VERSION 5.8 ;
BUSBITCHARS "[]" ;
DIVIDERCHAR "/" ;
UNITS
    DATABASE MICRONS 1000 ;
END UNITS

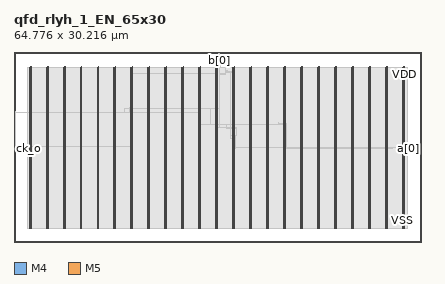
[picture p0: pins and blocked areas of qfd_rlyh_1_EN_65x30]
MACRO qfd_rlyh_1_EN_65x30
  FOREIGN qfd_rlyh_1_EN_65x30 0 0 ;
  CLASS BLOCK ;
  SIZE 64.776 BY 30.216 ;
  PIN a[0]
    DIRECTION INPUT ;
    USE SIGNAL ;
    PORT
      LAYER M4 ;
        RECT  64.692 14.928 64.776 14.952 ;
    END
  END a[0]
  PIN b[0]
    DIRECTION OUTPUT ;
    USE SIGNAL ;
    PORT
      LAYER M5 ;
        RECT  32.592 30.132 32.616 30.216 ;
    END
  END b[0]
  PIN ck_o
    DIRECTION OUTPUT ;
    USE SIGNAL ;
    PORT
      LAYER M4 ;
        RECT  0 14.928 0.084 14.952 ;
    END
  END ck_o
  PIN ckf
    DIRECTION INPUT ;
    USE SIGNAL ;
    PORT
      LAYER M4 ;
        RECT  0 15.024 0.084 15.048 ;
    END
  END ckf
  PIN ea
    DIRECTION INPUT ;
    USE SIGNAL ;
    PORT
      LAYER M4 ;
        RECT  64.692 15.024 64.776 15.048 ;
    END
  END ea
  PIN eb
    DIRECTION OUTPUT ;
    USE SIGNAL ;
    PORT
      LAYER M5 ;
        RECT  32.688 30.132 32.712 30.216 ;
    END
  END eb
  PIN VDD
    DIRECTION INOUT ;
    USE POWER ;
    PORT
      LAYER M5 ;
        RECT  61.992 2.151 62.112 27.833 ;
        RECT  59.292 2.151 59.412 27.833 ;
        RECT  56.592 2.151 56.712 27.833 ;
        RECT  53.892 2.151 54.012 27.833 ;
        RECT  51.192 2.151 51.312 27.833 ;
        RECT  48.492 2.151 48.612 27.833 ;
        RECT  45.792 2.151 45.912 27.833 ;
        RECT  43.092 2.151 43.212 27.833 ;
        RECT  40.392 2.151 40.512 27.833 ;
        RECT  37.692 2.151 37.812 27.833 ;
        RECT  34.992 2.151 35.112 27.833 ;
        RECT  32.292 2.151 32.412 27.833 ;
        RECT  29.592 2.151 29.712 27.833 ;
        RECT  26.892 2.151 27.012 27.833 ;
        RECT  24.192 2.151 24.312 27.833 ;
        RECT  21.492 2.151 21.612 27.833 ;
        RECT  18.792 2.151 18.912 27.833 ;
        RECT  16.092 2.151 16.212 27.833 ;
        RECT  13.392 2.151 13.512 27.833 ;
        RECT  10.692 2.151 10.812 27.833 ;
        RECT  7.992 2.151 8.112 27.833 ;
        RECT  5.292 2.151 5.412 27.833 ;
        RECT  2.592 2.151 2.712 27.833 ;
    END
  END VDD
  PIN VSS
    DIRECTION INOUT ;
    USE GROUND ;
    PORT
      LAYER M5 ;
        RECT  61.8 2.137 61.92 27.819 ;
        RECT  59.1 2.137 59.22 27.819 ;
        RECT  56.4 2.137 56.52 27.819 ;
        RECT  53.7 2.137 53.82 27.819 ;
        RECT  51 2.137 51.12 27.819 ;
        RECT  48.3 2.137 48.42 27.819 ;
        RECT  45.6 2.137 45.72 27.819 ;
        RECT  42.9 2.137 43.02 27.819 ;
        RECT  40.2 2.137 40.32 27.819 ;
        RECT  37.5 2.137 37.62 27.819 ;
        RECT  34.8 2.137 34.92 27.819 ;
        RECT  32.1 2.137 32.22 27.819 ;
        RECT  29.4 2.137 29.52 27.819 ;
        RECT  26.7 2.137 26.82 27.819 ;
        RECT  24 2.137 24.12 27.819 ;
        RECT  21.3 2.137 21.42 27.819 ;
        RECT  18.6 2.137 18.72 27.819 ;
        RECT  15.9 2.137 16.02 27.819 ;
        RECT  13.2 2.137 13.32 27.819 ;
        RECT  10.5 2.137 10.62 27.819 ;
        RECT  7.8 2.137 7.92 27.819 ;
        RECT  5.1 2.137 5.22 27.819 ;
        RECT  2.4 2.137 2.52 27.819 ;
    END
  END VSS
  # OT_OBS_CLOSED layer=M5 d_um=1.536 added=1
  OBS
    LAYER RVTN ;
     RECT  2.16 2.16 62.586 2.295 ;
     RECT  2.16 2.565 62.586 2.835 ;
     RECT  2.16 3.105 62.586 3.375 ;
     RECT  2.16 3.645 62.586 3.915 ;
     RECT  2.16 4.185 62.586 4.455 ;
     RECT  2.16 4.725 62.586 4.995 ;
     RECT  2.16 5.265 62.586 5.535 ;
     RECT  2.16 5.805 62.586 6.075 ;
     RECT  2.16 6.345 62.586 6.615 ;
     RECT  2.16 6.885 62.586 7.155 ;
     RECT  2.16 7.425 62.586 7.695 ;
     RECT  2.16 7.965 62.586 8.235 ;
     RECT  2.16 8.505 62.586 8.775 ;
     RECT  2.16 9.045 62.586 9.315 ;
     RECT  2.16 9.585 62.586 9.855 ;
     RECT  2.16 10.125 62.586 10.395 ;
     RECT  2.16 10.665 62.586 10.935 ;
     RECT  2.16 11.205 62.586 11.475 ;
     RECT  2.16 11.745 62.586 12.015 ;
     RECT  2.16 12.285 62.586 12.555 ;
     RECT  2.16 12.825 62.586 13.095 ;
     RECT  2.16 13.365 62.586 13.635 ;
     RECT  2.16 13.905 62.586 14.175 ;
     RECT  2.16 14.445 62.586 14.715 ;
     RECT  2.16 14.985 62.586 15.255 ;
     RECT  2.16 15.525 62.586 15.795 ;
     RECT  2.16 16.065 62.586 16.335 ;
     RECT  2.16 16.605 62.586 16.875 ;
     RECT  2.16 17.145 62.586 17.415 ;
     RECT  2.16 17.685 62.586 17.955 ;
     RECT  2.16 18.225 62.586 18.495 ;
     RECT  2.16 18.765 62.586 19.035 ;
     RECT  2.16 19.305 62.586 19.575 ;
     RECT  2.16 19.845 62.586 20.115 ;
     RECT  2.16 20.385 62.586 20.655 ;
     RECT  2.16 20.925 62.586 21.195 ;
     RECT  2.16 21.465 62.586 21.735 ;
     RECT  2.16 22.005 62.586 22.275 ;
     RECT  2.16 22.545 62.586 22.815 ;
     RECT  2.16 23.085 62.586 23.355 ;
     RECT  2.16 23.625 62.586 23.895 ;
     RECT  2.16 24.165 62.586 24.435 ;
     RECT  2.16 24.705 62.586 24.975 ;
     RECT  2.16 25.245 62.586 25.515 ;
     RECT  2.16 25.785 62.586 26.055 ;
     RECT  2.16 26.325 62.586 26.595 ;
     RECT  2.16 26.865 62.586 27.135 ;
     RECT  2.16 27.405 62.586 27.675 ;
    LAYER RVTP ;
     RECT  2.16 2.295 62.586 2.565 ;
     RECT  2.16 2.835 62.586 3.105 ;
     RECT  2.16 3.375 62.586 3.645 ;
     RECT  2.16 3.915 62.586 4.185 ;
     RECT  2.16 4.455 62.586 4.725 ;
     RECT  2.16 4.995 62.586 5.265 ;
     RECT  2.16 5.535 62.586 5.805 ;
     RECT  2.16 6.075 62.586 6.345 ;
     RECT  2.16 6.615 62.586 6.885 ;
     RECT  2.16 7.155 62.586 7.425 ;
     RECT  2.16 7.695 62.586 7.965 ;
     RECT  2.16 8.235 62.586 8.505 ;
     RECT  2.16 8.775 62.586 9.045 ;
     RECT  2.16 9.315 62.586 9.585 ;
     RECT  2.16 9.855 62.586 10.125 ;
     RECT  2.16 10.395 62.586 10.665 ;
     RECT  2.16 10.935 62.586 11.205 ;
     RECT  2.16 11.475 62.586 11.745 ;
     RECT  2.16 12.015 62.586 12.285 ;
     RECT  2.16 12.555 62.586 12.825 ;
     RECT  2.16 13.095 62.586 13.365 ;
     RECT  2.16 13.635 62.586 13.905 ;
     RECT  2.16 14.175 62.586 14.445 ;
     RECT  2.16 14.715 62.586 14.985 ;
     RECT  2.16 15.255 62.586 15.525 ;
     RECT  2.16 15.795 62.586 16.065 ;
     RECT  2.16 16.335 62.586 16.605 ;
     RECT  2.16 16.875 62.586 17.145 ;
     RECT  2.16 17.415 62.586 17.685 ;
     RECT  2.16 17.955 62.586 18.225 ;
     RECT  2.16 18.495 62.586 18.765 ;
     RECT  2.16 19.035 62.586 19.305 ;
     RECT  2.16 19.575 62.586 19.845 ;
     RECT  2.16 20.115 62.586 20.385 ;
     RECT  2.16 20.655 62.586 20.925 ;
     RECT  2.16 21.195 62.586 21.465 ;
     RECT  2.16 21.735 62.586 22.005 ;
     RECT  2.16 22.275 62.586 22.545 ;
     RECT  2.16 22.815 62.586 23.085 ;
     RECT  2.16 23.355 62.586 23.625 ;
     RECT  2.16 23.895 62.586 24.165 ;
     RECT  2.16 24.435 62.586 24.705 ;
     RECT  2.16 24.975 62.586 25.245 ;
     RECT  2.16 25.515 62.586 25.785 ;
     RECT  2.16 26.055 62.586 26.325 ;
     RECT  2.16 26.595 62.586 26.865 ;
     RECT  2.16 27.135 62.586 27.405 ;
     RECT  2.16 27.675 62.586 27.81 ;
    LAYER M1 ;
     RECT  2.16 2.151 62.586 27.819 ;
    LAYER M2 ;
     RECT  2.16 2.151 62.586 27.819 ;
     RECT  62.586 15.03 63.823 15.048 ;
     RECT  63.823 14.922 63.851 15.048 ;
     RECT  63.851 14.922 63.887 14.94 ;
    LAYER M3 ;
     RECT  2.415 2.143 2.505 2.413 ;
     RECT  5.115 2.143 5.205 2.413 ;
     RECT  7.815 2.143 7.905 2.413 ;
     RECT  10.515 2.143 10.605 2.413 ;
     RECT  13.215 2.143 13.305 2.413 ;
     RECT  15.915 2.143 16.005 2.413 ;
     RECT  18.615 2.143 18.705 2.413 ;
     RECT  21.315 2.143 21.405 2.413 ;
     RECT  24.015 2.143 24.105 2.413 ;
     RECT  26.715 2.143 26.805 2.413 ;
     RECT  29.415 2.143 29.505 2.413 ;
     RECT  32.115 2.143 32.205 2.413 ;
     RECT  34.815 2.143 34.905 2.413 ;
     RECT  37.515 2.143 37.605 2.413 ;
     RECT  40.215 2.143 40.305 2.413 ;
     RECT  42.915 2.143 43.005 2.413 ;
     RECT  45.615 2.143 45.705 2.413 ;
     RECT  48.315 2.143 48.405 2.413 ;
     RECT  51.015 2.143 51.105 2.413 ;
     RECT  53.715 2.143 53.805 2.413 ;
     RECT  56.415 2.143 56.505 2.413 ;
     RECT  59.115 2.143 59.205 2.413 ;
     RECT  61.815 2.143 61.905 2.413 ;
     RECT  34.815 2.413 35.097 14.881 ;
     RECT  56.415 2.413 56.697 14.881 ;
     RECT  59.115 2.413 59.397 14.881 ;
     RECT  59.115 14.881 60.138 14.917 ;
     RECT  59.112 14.917 60.138 14.957 ;
     RECT  63.828 14.917 63.882 14.957 ;
     RECT  59.115 14.957 60.138 15.017 ;
     RECT  55.872 14.881 56.697 15.053 ;
     RECT  59.115 15.017 59.634 15.053 ;
     RECT  63.828 14.957 63.846 15.053 ;
     RECT  2.415 2.413 2.697 15.151 ;
     RECT  5.115 2.413 5.397 15.151 ;
     RECT  10.515 2.413 10.797 15.151 ;
     RECT  13.215 2.413 13.497 15.151 ;
     RECT  5.004 15.151 5.397 15.197 ;
     RECT  10.404 15.151 10.797 15.197 ;
     RECT  13.104 15.151 13.497 15.197 ;
     RECT  2.415 15.151 2.718 15.251 ;
     RECT  34.815 14.881 35.19 16.411 ;
     RECT  34.452 16.411 35.19 16.951 ;
     RECT  34.452 16.951 35.334 18.121 ;
     RECT  33.732 18.121 35.334 18.221 ;
     RECT  42.915 2.413 43.197 18.523 ;
     RECT  42.915 18.523 43.254 18.845 ;
     RECT  42.048 18.661 42.066 18.959 ;
     RECT  30.852 20.635 30.87 20.849 ;
     RECT  17.532 21.091 17.55 21.197 ;
     RECT  31.176 21.001 31.194 21.197 ;
     RECT  18.615 2.413 18.897 21.271 ;
     RECT  18.468 21.271 18.897 21.341 ;
     RECT  32.115 2.413 32.397 26.671 ;
     RECT  32.115 26.671 33.606 26.789 ;
     RECT  33.588 26.789 33.606 26.833 ;
     RECT  32.115 26.789 32.778 26.861 ;
     RECT  33.588 26.833 33.714 26.941 ;
     RECT  34.452 18.221 35.097 26.941 ;
     RECT  33.588 26.941 35.097 27.059 ;
     RECT  33.588 27.059 33.966 27.329 ;
     RECT  2.415 15.251 2.697 27.557 ;
     RECT  5.115 15.197 5.397 27.557 ;
     RECT  7.815 2.413 8.097 27.557 ;
     RECT  10.515 15.197 10.797 27.557 ;
     RECT  13.215 15.197 13.497 27.557 ;
     RECT  15.915 2.413 16.197 27.557 ;
     RECT  18.615 21.341 18.897 27.557 ;
     RECT  21.315 2.413 21.597 27.557 ;
     RECT  24.015 2.413 24.297 27.557 ;
     RECT  26.715 2.413 26.997 27.557 ;
     RECT  29.415 2.413 29.697 27.557 ;
     RECT  32.115 26.861 32.397 27.557 ;
     RECT  34.815 27.059 35.097 27.557 ;
     RECT  37.515 2.413 37.797 27.557 ;
     RECT  40.215 2.413 40.497 27.557 ;
     RECT  42.915 18.845 43.197 27.557 ;
     RECT  45.615 2.413 45.897 27.557 ;
     RECT  48.315 2.413 48.597 27.557 ;
     RECT  51.015 2.413 51.297 27.557 ;
     RECT  53.715 2.413 53.997 27.557 ;
     RECT  56.415 15.053 56.697 27.557 ;
     RECT  59.115 15.053 59.397 27.557 ;
     RECT  61.815 2.413 62.097 27.557 ;
     RECT  33.588 27.329 33.606 27.635 ;
     RECT  32.307 27.557 32.397 27.751 ;
     RECT  2.607 27.557 2.697 27.827 ;
     RECT  5.307 27.557 5.397 27.827 ;
     RECT  8.007 27.557 8.097 27.827 ;
     RECT  10.707 27.557 10.797 27.827 ;
     RECT  13.407 27.557 13.497 27.827 ;
     RECT  16.107 27.557 16.197 27.827 ;
     RECT  18.807 27.557 18.897 27.827 ;
     RECT  21.507 27.557 21.597 27.827 ;
     RECT  24.207 27.557 24.297 27.827 ;
     RECT  26.907 27.557 26.997 27.827 ;
     RECT  29.607 27.557 29.697 27.827 ;
     RECT  32.307 27.751 32.814 27.827 ;
     RECT  35.007 27.557 35.097 27.827 ;
     RECT  37.707 27.557 37.797 27.827 ;
     RECT  40.407 27.557 40.497 27.827 ;
     RECT  43.107 27.557 43.197 27.827 ;
     RECT  45.807 27.557 45.897 27.827 ;
     RECT  48.507 27.557 48.597 27.827 ;
     RECT  51.207 27.557 51.297 27.827 ;
     RECT  53.907 27.557 53.997 27.827 ;
     RECT  56.607 27.557 56.697 27.827 ;
     RECT  59.307 27.557 59.397 27.827 ;
     RECT  62.007 27.557 62.097 27.827 ;
     RECT  32.796 27.827 32.814 29.069 ;
    LAYER M4 ;
     RECT  0.084 14.928 0.227 14.952 ;
     RECT  0.06 14.952 0.227 15.024 ;
     RECT  0.084 15.024 0.227 15.048 ;
     RECT  0.227 14.928 2.408 14.952 ;
     RECT  0.181 20.64 2.408 20.664 ;
     RECT  2.408 2.148 2.512 27.552 ;
     RECT  2.512 2.418 2.6 27.552 ;
     RECT  2.6 2.418 2.704 27.822 ;
     RECT  2.704 15.168 5.108 15.192 ;
     RECT  2.704 20.64 5.108 20.664 ;
     RECT  5.108 2.148 5.212 27.552 ;
     RECT  5.212 2.418 5.3 27.552 ;
     RECT  5.3 2.418 5.404 27.822 ;
     RECT  5.404 15.168 7.808 15.192 ;
     RECT  5.404 20.64 7.808 20.664 ;
     RECT  7.808 2.148 7.912 27.552 ;
     RECT  7.912 2.418 8 27.552 ;
     RECT  8 2.418 8.104 27.822 ;
     RECT  8.104 15.168 10.508 15.192 ;
     RECT  8.104 20.64 10.508 20.664 ;
     RECT  10.508 2.148 10.612 27.552 ;
     RECT  10.612 2.418 10.7 27.552 ;
     RECT  10.7 2.418 10.804 27.822 ;
     RECT  10.804 15.168 13.208 15.192 ;
     RECT  10.804 20.64 13.208 20.664 ;
     RECT  13.208 2.148 13.312 27.552 ;
     RECT  13.312 2.418 13.4 27.552 ;
     RECT  13.4 2.418 13.504 27.822 ;
     RECT  13.504 15.168 15.908 15.192 ;
     RECT  13.504 20.64 15.908 20.664 ;
     RECT  15.908 2.148 16.012 27.552 ;
     RECT  16.012 2.418 16.1 27.552 ;
     RECT  16.1 2.418 16.204 27.822 ;
     RECT  16.204 20.64 17.521 20.664 ;
     RECT  17.521 20.64 18.428 21.192 ;
     RECT  16.204 15.168 18.608 15.192 ;
     RECT  18.428 20.64 18.608 21.336 ;
     RECT  18.469 26.832 18.608 26.856 ;
     RECT  18.608 2.148 18.712 27.552 ;
     RECT  18.712 2.418 18.8 27.552 ;
     RECT  18.8 2.418 18.904 27.822 ;
     RECT  18.904 20.64 21.308 21.192 ;
     RECT  18.904 26.832 21.308 26.856 ;
     RECT  21.308 2.148 21.412 27.552 ;
     RECT  21.412 2.418 21.5 27.552 ;
     RECT  21.5 2.418 21.604 27.822 ;
     RECT  21.604 20.64 24.008 21.192 ;
     RECT  21.604 26.832 24.008 26.856 ;
     RECT  24.008 2.148 24.112 27.552 ;
     RECT  24.112 2.418 24.2 27.552 ;
     RECT  24.2 2.418 24.304 27.822 ;
     RECT  24.304 20.64 26.708 21.192 ;
     RECT  24.304 26.832 26.708 26.856 ;
     RECT  26.708 2.148 26.812 27.552 ;
     RECT  26.812 2.418 26.9 27.552 ;
     RECT  26.9 2.418 27.004 27.822 ;
     RECT  27.004 20.64 29.408 21.192 ;
     RECT  27.004 26.832 29.408 26.856 ;
     RECT  29.408 2.148 29.512 27.552 ;
     RECT  29.512 2.418 29.6 27.552 ;
     RECT  29.6 2.418 29.704 27.822 ;
     RECT  29.704 20.64 30.881 21.192 ;
     RECT  31.189 18.72 32.108 18.744 ;
     RECT  30.881 21.168 32.108 21.192 ;
     RECT  29.704 26.832 32.108 26.856 ;
     RECT  32.108 2.148 32.212 27.552 ;
     RECT  32.212 2.418 32.3 27.552 ;
     RECT  32.3 2.418 32.404 27.822 ;
     RECT  32.404 26.832 32.789 26.856 ;
     RECT  32.677 29.04 32.825 29.064 ;
     RECT  32.404 18.192 33.761 18.744 ;
     RECT  33.761 18.72 34.808 18.744 ;
     RECT  34.808 2.148 34.912 27.552 ;
     RECT  34.912 2.418 35 27.552 ;
     RECT  35 2.418 35.104 27.822 ;
     RECT  35.104 15.024 37.508 15.048 ;
     RECT  35.104 18.72 37.508 18.744 ;
     RECT  37.508 2.148 37.612 27.552 ;
     RECT  37.612 2.418 37.7 27.552 ;
     RECT  37.7 2.418 37.804 27.822 ;
     RECT  37.804 15.024 40.208 15.048 ;
     RECT  37.804 18.72 40.208 18.744 ;
     RECT  40.208 2.148 40.312 27.552 ;
     RECT  40.312 2.418 40.4 27.552 ;
     RECT  40.4 2.418 40.504 27.822 ;
     RECT  40.504 18.72 42.037 18.744 ;
     RECT  40.504 15.024 42.908 15.048 ;
     RECT  42.037 18.72 42.908 18.84 ;
     RECT  42.908 2.148 43.012 27.552 ;
     RECT  43.012 2.418 43.1 27.552 ;
     RECT  43.1 2.418 43.204 27.822 ;
     RECT  43.204 18.528 43.265 18.84 ;
     RECT  43.265 18.528 43.331 18.552 ;
     RECT  43.204 14.928 45.608 15.048 ;
     RECT  45.608 2.148 45.712 27.552 ;
     RECT  45.712 2.418 45.8 27.552 ;
     RECT  45.8 2.418 45.904 27.822 ;
     RECT  45.904 14.928 48.308 15.048 ;
     RECT  48.308 2.148 48.412 27.552 ;
     RECT  48.412 2.418 48.5 27.552 ;
     RECT  48.5 2.418 48.604 27.822 ;
     RECT  48.604 14.928 51.008 15.048 ;
     RECT  51.008 2.148 51.112 27.552 ;
     RECT  51.112 2.418 51.2 27.552 ;
     RECT  51.2 2.418 51.304 27.822 ;
     RECT  51.304 14.928 53.708 15.048 ;
     RECT  53.708 2.148 53.812 27.552 ;
     RECT  53.812 2.418 53.9 27.552 ;
     RECT  53.9 2.418 54.004 27.822 ;
     RECT  54.004 14.928 56.408 15.048 ;
     RECT  56.408 2.148 56.512 27.552 ;
     RECT  56.512 2.418 56.6 27.552 ;
     RECT  56.6 2.418 56.704 27.822 ;
     RECT  56.704 14.928 59.108 15.048 ;
     RECT  59.108 2.148 59.212 27.552 ;
     RECT  59.212 2.418 59.3 27.552 ;
     RECT  59.3 2.418 59.404 27.822 ;
     RECT  59.404 15.024 61.808 15.048 ;
     RECT  61.808 2.148 61.912 27.552 ;
     RECT  61.912 2.418 62 27.552 ;
     RECT  62 2.418 62.104 27.822 ;
     RECT  62.104 15.024 63.853 15.048 ;
     RECT  63.853 14.928 64.692 14.952 ;
     RECT  63.853 14.952 64.716 15.024 ;
     RECT  63.853 15.024 64.692 15.048 ;
    LAYER M5 ;
     RECT  2.4 2.137 2.52 2.151 ;
     RECT  5.1 2.137 5.22 2.151 ;
     RECT  7.8 2.137 7.92 2.151 ;
     RECT  10.5 2.137 10.62 2.151 ;
     RECT  13.2 2.137 13.32 2.151 ;
     RECT  15.9 2.137 16.02 2.151 ;
     RECT  18.6 2.137 18.72 2.151 ;
     RECT  21.3 2.137 21.42 2.151 ;
     RECT  24 2.137 24.12 2.151 ;
     RECT  26.7 2.137 26.82 2.151 ;
     RECT  29.4 2.137 29.52 2.151 ;
     RECT  32.1 2.137 32.22 2.151 ;
     RECT  34.8 2.137 34.92 2.151 ;
     RECT  37.5 2.137 37.62 2.151 ;
     RECT  40.2 2.137 40.32 2.151 ;
     RECT  42.9 2.137 43.02 2.151 ;
     RECT  45.6 2.137 45.72 2.151 ;
     RECT  48.3 2.137 48.42 2.151 ;
     RECT  51 2.137 51.12 2.151 ;
     RECT  53.7 2.137 53.82 2.151 ;
     RECT  56.4 2.137 56.52 2.151 ;
     RECT  59.1 2.137 59.22 2.151 ;
     RECT  61.8 2.137 61.92 2.151 ;
     RECT  42.9 2.151 43.212 14.917 ;
     RECT  18.6 2.151 18.912 15.157 ;
     RECT  32.1 2.151 32.412 18.181 ;
     RECT  42.9 14.917 43.32 18.563 ;
     RECT  32.1 18.181 32.616 18.709 ;
     RECT  0.192 15.013 0.216 20.675 ;
     RECT  31.2 18.709 32.616 21.203 ;
     RECT  18.48 15.157 18.912 26.867 ;
     RECT  2.4 2.151 2.712 27.819 ;
     RECT  5.1 2.151 5.412 27.819 ;
     RECT  7.8 2.151 8.112 27.819 ;
     RECT  10.5 2.151 10.812 27.819 ;
     RECT  13.2 2.151 13.512 27.819 ;
     RECT  15.9 2.151 16.212 27.819 ;
     RECT  18.6 26.867 18.912 27.819 ;
     RECT  21.3 2.151 21.612 27.819 ;
     RECT  24 2.151 24.312 27.819 ;
     RECT  26.7 2.151 27.012 27.819 ;
     RECT  29.4 2.151 29.712 27.819 ;
     RECT  32.1 21.203 32.616 27.819 ;
     RECT  34.8 2.151 35.112 27.819 ;
     RECT  37.5 2.151 37.812 27.819 ;
     RECT  40.2 2.151 40.512 27.819 ;
     RECT  42.9 18.563 43.212 27.819 ;
     RECT  45.6 2.151 45.912 27.819 ;
     RECT  48.3 2.151 48.612 27.819 ;
     RECT  51 2.151 51.312 27.819 ;
     RECT  53.7 2.151 54.012 27.819 ;
     RECT  56.4 2.151 56.712 27.819 ;
     RECT  59.1 2.151 59.412 27.819 ;
     RECT  61.8 2.151 62.112 27.819 ;
     RECT  2.592 27.819 2.712 27.833 ;
     RECT  5.292 27.819 5.412 27.833 ;
     RECT  7.992 27.819 8.112 27.833 ;
     RECT  10.692 27.819 10.812 27.833 ;
     RECT  13.392 27.819 13.512 27.833 ;
     RECT  16.092 27.819 16.212 27.833 ;
     RECT  18.792 27.819 18.912 27.833 ;
     RECT  21.492 27.819 21.612 27.833 ;
     RECT  24.192 27.819 24.312 27.833 ;
     RECT  26.892 27.819 27.012 27.833 ;
     RECT  29.592 27.819 29.712 27.833 ;
     RECT  32.292 27.819 32.616 27.833 ;
     RECT  34.992 27.819 35.112 27.833 ;
     RECT  37.692 27.819 37.812 27.833 ;
     RECT  40.392 27.819 40.512 27.833 ;
     RECT  43.092 27.819 43.212 27.833 ;
     RECT  45.792 27.819 45.912 27.833 ;
     RECT  48.492 27.819 48.612 27.833 ;
     RECT  51.192 27.819 51.312 27.833 ;
     RECT  53.892 27.819 54.012 27.833 ;
     RECT  56.592 27.819 56.712 27.833 ;
     RECT  59.292 27.819 59.412 27.833 ;
     RECT  61.992 27.819 62.112 27.833 ;
     RECT  32.592 27.833 32.616 29.029 ;
     RECT  32.592 29.029 32.712 30.132 ;
     RECT  32.616 30.132 32.688 30.16 ;
     RECT  29.712 18.709 31.2 21.203 ;
  END
END qfd_rlyh_1_EN_65x30
END LIBRARY
